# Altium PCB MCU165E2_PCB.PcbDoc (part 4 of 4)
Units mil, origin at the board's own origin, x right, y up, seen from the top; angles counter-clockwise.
Board outline 2658.83 x 2179.35 mil, 6 copper layers (Top Signal Layer, GND1, Mid Layer, PWR, GND2, Bottom Signal Layer), stack 60.4 mil thick; 226 components, 197 nets, 947 pads, 562 vias.
Unrouted connection lines stored in the file: 81.

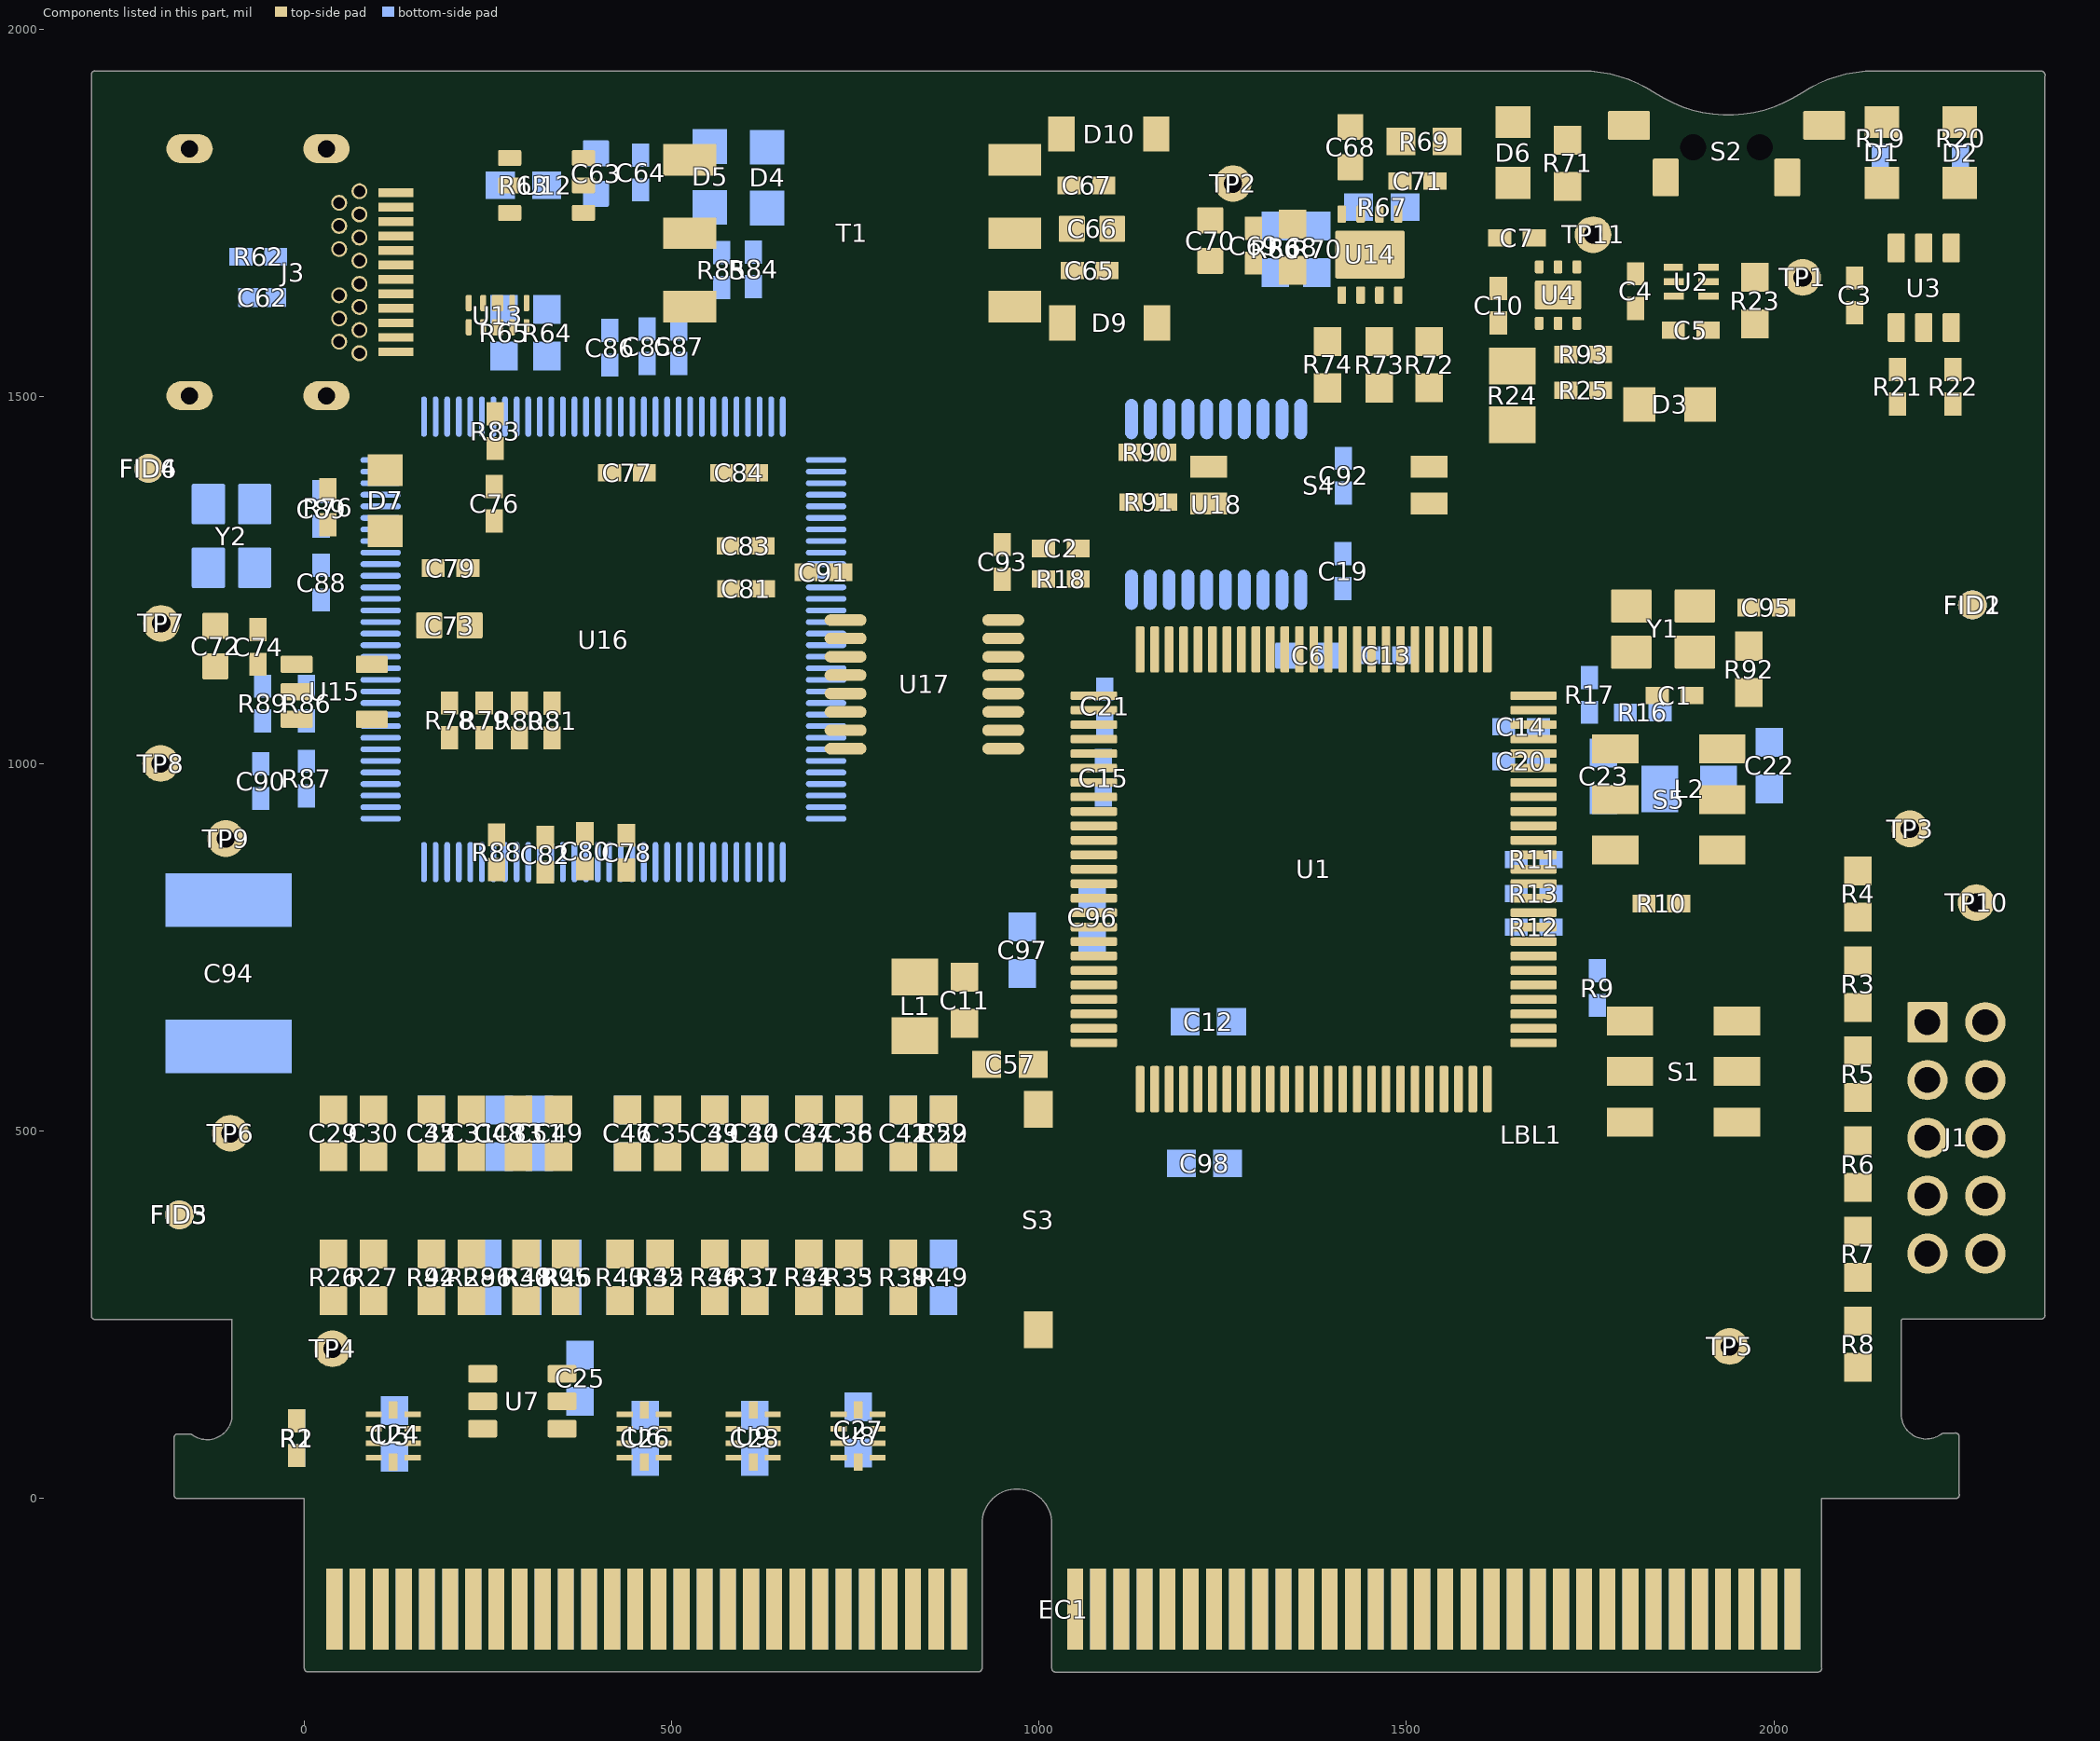
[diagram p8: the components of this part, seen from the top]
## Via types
v1: diameter 19.68, hole 9.84, Top Signal Layer to Bottom Signal Layer, tented both sides, 540 vias
v2: diameter 23.62, hole 11.81, Top Signal Layer to Bottom Signal Layer, tented both sides, 16 vias
v3: diameter 19.68, hole 7.99, Top Signal Layer to Bottom Signal Layer, tented bottom, 4 vias
v4: diameter 19.68, hole 7.87, Top Signal Layer to Bottom Signal Layer, tented bottom, 2 vias

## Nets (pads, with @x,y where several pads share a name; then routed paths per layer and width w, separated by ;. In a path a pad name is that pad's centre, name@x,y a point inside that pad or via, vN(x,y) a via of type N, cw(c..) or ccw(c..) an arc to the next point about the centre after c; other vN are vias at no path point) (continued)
pads on no net: EC1.4 EC1.32 EC1.41 EC1.42 EC1.43 EC1.44 EC1.66 EC1.110 EC1.113 EC1.114 EC1.115 EC1.116 EC1.117 FID1.1 FID2.1 FID3.1 FID4.1 FID5.1 FID6.1 J1.9 J3.A2 J3.A3 J3.A8 J3.A10 J3.A11 J3.B2 J3.B3 J3.B8 J3.B10 J3.B11 LBL1.0 S2. U2.6 U4.7@1688.57,1637.76 U4.7@1724,1637.76 U5.4 U5.9 U6.4 U6.9 U7.6 U8.4 U8.9 U9.4 U9.8 U9.9 U13.3@263.14,1594.13 U13.8@263.14,1627 U14.9@1425.58,1692.88 U14.9@1475.19,1692.88 U16.1 U16.2 U16.5 U16.6 U16.11 U16.12 U16.13 U16.14 U16.15 U16.18 U16.19 U16.20 U16.21 U16.22 U16.23 U16.24 U16.25 U16.27 U16.29 U16.30 U16.31 U16.32 U16.41 U16.42 U16.43 U16.44 U16.45 U16.46 U16.49 U16.50 U16.53 U16.54 U16.56 U16.57 U16.65 U16.67 U16.71 U16.72 U16.73 U16.74 U16.75 U16.76 U16.77 U16.78 U16.81 U16.82 U16.83 U16.84 U16.85 U16.86 U16.91 U16.92 U16.95 U16.102 U16.103 U16.104 U16.105 U16.106 U16.107 U16.108 U16.109 U16.110 U16.111 U16.112 U16.116 U16.117 U16.118 U16.119 U16.120 U16.121 U16.123 U16.124 U16.125 U16.126 U16.127 U16.128 U18.3 U18.5

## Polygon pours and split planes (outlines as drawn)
EMU_GND on GND1 "GND1_EMU_GND_P002" (solid, remove dead copper, pour order 2): -263.59,1927.66 768,1927.66 768,946.16 619.85,798 -265.76,798
GND on GND1 "GND1-GND" (solid, remove dead copper, pour order 34): 928,1947 928,888 680,640 -290.58,640 -290.58,242.58 -286,238 -100,238 -100,118 -96,114 -126,84 -126,80 -174,80 -177,83 -177,1 -3.04,1 -1,-1.04 -1,-241 2054.73,-241 2067,-228.73 2067,-0.11 2255.11,-0.11 2253,2 2253,88 2219,88 2211,80 2192,80 2175,97 2175,244.19 2364.19,244.19 2369,249 2369,1941 2363,1947 929,1947
EMU_5V0 on PWR "PWR_EMU_5V0_P006" (solid, remove dead copper, pour order 6): -264.49,1917.16 761,1917.16 761,1589.15 733.01,1561.16 190.16,1561.16 -48,1323 -48,1082 -68,1062 -236,1062 -262.82,1088.82 -262.74,1913.9
VDD_1V2 on PWR "PWR-No Net 1" (solid, remove dead copper, pour order 54): 1616,209.78 1616,113 1623.45,105.55 1730.45,105.55 1939,-103 1949,-113 2025,-113 2034,-104 2034,-72.82 1957.32,3.86 1957.32,149.68 1931,176 1851.42,176 1838.42,189 1772.18,189 1679.18,282 1633.1,282 1620.16,282 1603.92,265.76 1603.92,219 1606.78,219
3V3 on PWR "PWR-3V3" (solid, remove dead copper, pour order 20): 1148.99,1266.6 1066.72,1184.33 1066.72,969.47 974.21,876.96 974.21,794.21 870,690 870,668 845,643 683,643 914.85,874.85 914.85,1465.09 993.25,1543.49 1743.57,1543.49 1838,1637.92 1838,1853.1 1859.71,1874.81 2334,1874.81 2334,88.13 2267.87,22 2068.46,22 2067,23.46 2046,2.46 2046,-27 2027,-46 2009,-46 1964,-1 1964,133 1964,175.98 1755.54,384.44 1755.54,1266.6
VDD_1V2 on PWR "PWR-VDD_1V2" (solid, remove dead copper, pour order 30): 1529.46,408.54 1445,493 1445,528 1347,626 1347,629 1309,629 1254,629 1194.43,688.57 1194.43,810.03 1093.39,911.07 1093.39,1047.83 1142.64,1097.08 1745.19,1097.08 1745.19,355.02 1940.32,159.89 1940.32,105.55 1623.3,105.55 1576.52,152.33 1529.46,199.39
EMU_3V3 on PWR "PWR-No Net" (solid, remove dead copper, pour order 8): -290.79,798 619.85,798 774,952.15 774,1495 723,1546 201,1546 -24,1321 -24,1079.29 -57.29,1046 -286.12,1046 -291.12,1041
ISO_Pout_5V0 on PWR "PWR_ISO_POUT_5V0_P056" (solid, remove dead copper, pour order 56): 1104.2,1913 1076.52,1885.32 1076.52,1833.73 1094.5,1815.75 1505.14,1815.75 1513.53,1824.14 1513.53,1897.03 1497.56,1913
5V0 on PWR "PWR_5V0_P058" (solid, remove dead copper, pour order 58): 1561.53,1850.06 1543.49,1832.02 1543.49,1663.96 1551.87,1655.58 1784.24,1655.58 1814.03,1685.37 1814.03,1842.19 1806.16,1850.06
VDDIO_3V3 on PWR "PWR_VDDIO_3V3_P026" (solid, remove dead copper, pour order 26): 1084.77,1057.96 1096.91,1045.82 1174.29,1045.82 1241.1,1112.63 1611.63,1112.63 1624.42,1099.84 1624.42,982.4 1685.6,921.22 1738,921.22 1769.97,953.19 1769.97,1223.26 1737.69,1255.54 1151.49,1255.54 1084.77,1188.82
VDDA_3V3 on PWR "PWR_VDDA_3V3_P014" (solid, remove dead copper, pour order 14): 831.34,607.61 1125.77,607.61 1255.04,736.88 1348.85,736.88 1465.5,620.23 1465.5,470.95 1456.55,462 896.75,462 818.98,539.77 818.98,598.84
HSEC_5V0 on PWR "PWR-HSEC_5V0" (solid, remove dead copper, pour order 16): 490,580 490,581 738.56,581 771.71,614.15 865.52,614.15 1120.02,614.15 1219.24,713.37 1219.24,789.39 1088.72,919.91 1010.65,919.91 996.7,905.96 996.7,899.68 963,860 961,857 950,857 950,832 874,756 874,718 786,718 785.5,718.5 705,638 6,638 -75,557 -75,51 -37,13 0,13 0,-196 32.97,-228.97 854.03,-228.97 886,-197 886,-76.37 886.86,-11.9 919.07,18.93 937.29,37.15 996.7,37.15 1036,-2.15 1036,-90.41 1058.59,-113 1883.29,-113 1894.59,-101.7 1894.59,-76.59 1720,98 1615,98 1539.83,173.17 1420.83,173.17 1415,179 937,179 934,182 834.51,82.51 832.49,82.51 702,-47 596,-47 593,-44 210,-44 168.15,-2.15 119.15,-2.15 41.83,75.17 41.83,176.17 10,208 10,533.4 56.6,580
VDDA_3V3 on PWR "PWR-VDDA_3V3" (solid, remove dead copper, pour order 12): 495,579 1377.07,579 1444,512.07 1444,481.73 1512.87,412.59 1512.87,194.36 1496.51,178 954.96,178 848,71.04 745,-31.96 745,-102 734,-113 189,-113 171.63,-95.63 171.63,-52.75 47,71.88 47,172 2,217 2,525.4 55.6,579
ISO_Pout_5V0 on Top Signal Layer "TOP_SIGNAL_LAYER_ISO_POUT_5V0_P010" (solid, remove dead copper, pour order 10): 1066.33,1586.96 1087.82,1565.46 1162.46,1565.46 1171.46,1574.46 1171.46,1916.59 1169.58,1918.47 1094.46,1918.46 1066.33,1890.33
EMU_GND on Top Signal Layer "TOP_SIGNAL_LAYER_EMU_GND_P050" (solid, remove dead copper, pour order 50): -263.59,1927.66 768,1927.66 768,946.16 619.85,798 -265.76,798
GND on Top Signal Layer "Top Signal Layer-GND" (solid, remove dead copper, pour order 62): 930.87,1940.66 930.87,882.87 681.66,633.66 -287.71,633.66 -287.71,236.24 -283.13,231.66 -97.13,231.66 -97.13,111.66 -93.13,107.66 -123.13,77.66 -123.13,73.66 -171.13,73.66 -174.13,76.66 -174.13,-5.34 -0.17,-5.34 1.87,-7.37 1.87,-247.34 2057.59,-247.34 2069.87,-235.06 2069.87,-6.45 2257.98,-6.45 2255.87,-4.34 2255.87,81.66 2221.87,81.66 2213.87,73.66 2194.87,73.66 2177.87,90.66 2177.87,237.86 2367.06,237.86 2371.87,242.66 2371.87,1934.66 2365.87,1940.66 931.87,1940.66
EMU_GND on Mid Layer "MID_LAYER_EMU_GND_P042" (solid, remove dead copper, pour order 42): -263.59,1927.66 768,1927.66 768,946.16 619.85,798 -265.76,798
HSEC_5V0 on Mid Layer "Mid Layer-HSEC_5V0" (solid, remove dead copper, pour order 32): 921.49,846.51 932.13,835.87 1182.87,835.87 1188,841 1188,1851.81 1160.81,1879 942.29,1879 921.49,1858.21
EMU_GND on GND2 "GND2_EMU_GND_P036" (solid, remove dead copper, pour order 36): -263.59,1927.66 768,1927.66 768,946.16 619.85,798 -265.76,798
GND on GND2 "GND2-GND" (solid, remove dead copper, pour order 40): 928,1947 928,888 680,640 -290.58,640 -290.58,242.58 -286,238 -100,238 -100,118 -96,114 -126,84 -126,80 -174,80 -177,83 -177,1 -3.04,1 -1,-1.04 -1,-241 2054.73,-241 2067,-228.73 2067,-0.11 2255.11,-0.11 2253,2 2253,88 2219,88 2211,80 2192,80 2175,97 2175,244.19 2364.19,244.19 2369,249 2369,1941 2363,1947 929,1947
EMU_GND on Bottom Signal Layer "BOTTOM_SIGNAL_LAYER_EMU_GND_P052" (solid, remove dead copper, pour order 52): -260.52,1943.12 771.07,1943.12 771.07,961.62 608.45,799 -262.72,799
GND on Bottom Signal Layer "Bottom Signal Layer-GND" (solid, remove dead copper, pour order 60): 928,1947 928,888 680,640 -290.58,640 -290.58,242.58 -286,238 -100,238 -100,118 -96,114 -126,84 -126,80 -174,80 -177,83 -177,1 -3.04,1 -1,-1.04 -1,-241 2054.73,-241 2067,-228.73 2067,-0.11 2255.11,-0.11 2253,2 2253,88 2219,88 2211,80 2192,80 2175,97 2175,244.19 2364.19,244.19 2369,249 2369,1941 2363,1947 929,1947

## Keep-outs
Keep-Out Layer:
  lines w7.87: 1737,1943 -284.72,1942.99 ccw(c-284.72,1937.99) -289.73,1937.99 -289.73,248.71 ccw(c-284.72,248.71) -284.72,243.7 -98.32,243.7 -98.32,115.84 cw(c-124,114.26) -98.27,113.93 cw(c-132.25,113.92) -152.76,86.83 ccw(c-155.74,82.96) -155.78,87.84 -172.11,87.84 ccw(c-172.15,82.91) -175.66,86.37 ccw(c-172.11,82.73) -177.19,82.76 -177.19,4.84 ccw(c-172.19,4.83) -171.02,-0.04 0.06,-0.04 0.06,-231.05 ccw(c5.07,-231.05) 5.9,-236 917.4,-236 ccw(c917.4,-230.98) 922.42,-230.98 922.42,-34.1 cw(c969.9,-34.49) 1017.39,-34.1 1017.39,-231.27 ccw(c1022.39,-231.28) 1018.85,-234.82 ccw(c1022.51,-231.22) 1022.46,-236.35 2060.22,-236.28 ccw(c2060.22,-231.26) 2065.23,-231.26 2065.16,-230.44 2065.16,-0.11 2247.39,-0.11 ccw(c2247.39,4.91) 2252.41,4.91 ccw(c2247.65,4.92) 2252.2,6.32 ; 1738,1943 cw(c1738,1761.33) 1838,1913 ccw(c1938,2064.67) 2038,1913 cw(c2138,1761.33) 2138,1943 2363.01,1943 cw(c2362.92,1936.82) 2369,1935.72 2369,249.2 cw(c2364,249.2) 2364,244.19 2174.88,244.19 2173.42,242.73 2173.42,114.71 ccw(c2207.4,114.83) 2227.9,87.73 ; 2227.9,87.72 cw(c2230.91,83.8) 2230.93,88.74 2245.21,88.74 cw(c2247.2,84.13) 2252.2,84.13 2252.2,6.33
  text ".Layer_Name" at -3605.96,-2857.09 h60

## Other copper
Top Signal Layer:
  pour cut-out: 717.58,294.2 710.51,294.2 707.35,291.03 705.7,291.03 705.7,281.5 713.9,273.3 718.73,273.3 718.73,274.42 723.13,278.82 722.94,279.01 722.94,287.47 723.04,287.57
  pour cut-out: 710.51,311.44 710.51,294.2 709.08,292.76 692.26,292.76 692.26,304.88 685.87,311.27
  pour cut-out: 16.11,357.26 16.11,244.89 117.97,244.89 117.97,357.25
  pour cut-out: 2168.19,1434.65 2243.2,1434.65 2231.04,1446.81 2231.04,1457.24 2192.82,1457.24 2187.39,1451.81
  pour cut-out: 2260.27,1557.52 2260.27,1510.27 2151.38,1510.13 2151.38,1569.96 2157.32,1575.9 2258.35,1575.9 2258.35,1559.44
  pour cut-out: 1148.95,1293.4 1148.95,1318.66 1138.63,1328.98 1122.61,1328.98 1110.89,1317.26 1110.89,1302.87 1115.34,1298.42
  pour cut-out: 1293.6,1423.94 1298.07,1419.46 1298.07,1372.26 1285,1359.19 1254.82,1359.19 1254.82,1414.97 1252.36,1417.43 1258.87,1423.94
  pour cut-out: 2164.32,289.95 2162.6,291.67 2150.19,291.67 2150.19,303.26 2155.96,309.03 2156.93,308.06 2171.39,308.06 2171.39,300.07 2172.71,298.75 2164.32,290.36
  pour cut-out: 2138.05,216.86 2138.05,203.23 2118.32,203.23 2115.25,206.3 2118.09,209.14 2118.09,218.81
  pour cut-out: 322.26,553.18 322.26,440.82 424.13,440.82 424.13,553.18
  pour cut-out: 470.72,553.18 470.72,440.82 572.59,440.82 572.59,553.18
  pour cut-out: 589.18,553.18 589.18,440.82 691.05,440.82 691.05,553.18
  pour cut-out: 717.64,553.18 717.64,440.82 897.07,440.82 897.07,553.18
  pour cut-out: 663.18,553.18 663.18,440.82 765.04,440.82 765.04,553.18
  pour cut-out: 534.72,553.18 534.72,440.82 636.58,440.82 636.58,553.18
  pour cut-out: 416.25,553.18 416.25,440.82 518.12,440.82 518.12,553.18
  pour cut-out: 267.79,553.18 267.79,440.82 369.66,440.82 369.66,553.18
  pour cut-out: 149.33,553.18 149.33,440.82 251.2,440.82 251.2,553.18
  pour cut-out: 16.11,553.18 16.11,440.82 117.97,440.82 117.97,553.18
  region net ISO_Pout_5V0: 1130.29,1896.55 1130.29,1825.69 1141.94,1814.04 1155.88,1827.98 1171.46,1827.98 1171.46,1886.02 1160.8,1896.68 1144.32,1896.68
  pour cut-out: 1026.79,1309.74 1037.32,1309.74 1037.32,1258.84 1021.72,1258.84 1021.72,1309.63
  pour cut-out: 1104.38,1440.48 1104.38,1331.76 1105.22,1330.92 1173.51,1330.92 1173.51,1440.48
  region net GND: 1408.09,1725.18 1532.31,1725.18 1540.67,1716.82 1540.67,1672.52 1528.84,1660.69 1384.45,1660.69 1371.83,1673.31 1375.3,1676.78 1375.3,1717.92 1382.54,1725.16 1406.56,1725.16
  region net GND: 1661.26,1662.02 1654.11,1654.87 1654.11,1621.74 1661.84,1614.01 1757.92,1614.01 1760.7,1616.79 1760.7,1651.46 1750.14,1662.02
  region net 3V3: 1612.68,1482.55 1612.68,1436.9 1608.15,1432.37 1608.15,1412.17 1611.33,1408.99 1686.1,1408.99 1690.04,1412.93 1690.04,1425.14 1675.46,1439.72 1675.46,1478.02 1671.18,1482.3
  region net VDDA_3V3: 850.17,662.7 792.62,662.7 775.26,645.34 775.26,591.94 781.27,585.93 842.7,585.93 862.33,605.56 862.33,656.4 855.96,662.77
  region net 3V3: 824.19,770.62 887.67,770.62 912.76,745.53 912.76,689.39 907.37,684 802.56,684 794.92,691.64 794.92,741.35
  region net 5V0: 1868.84,1660.87 1846.95,1660.87 1837.07,1670.75 1819.58,1670.75 1815.6,1666.77 1831.27,1651.1 1867.06,1651.1 1868.82,1652.86
  region net NetC10_1: 1659.98,1608.22 1652.69,1615.51 1613.82,1615.51 1612.12,1613.81 1612.12,1518.43 1614.01,1516.54 1675.43,1516.54 1695.18,1496.79 1729.78,1496.79 1732.8,1499.81 1732.8,1568.37 1721.33,1579.84 1694.96,1579.84 1686.52,1588.28 1686.52,1606.55 1684.85,1608.22
  region net 5V0: 1767.97,1744.87 1784.37,1744.87 1837.07,1692.17 1837.07,1656.9 1831.27,1651.1 1798.39,1651.1 1782.06,1667.43 1733.85,1667.43 1730.91,1670.37 1730.91,1731.23 1744.57,1744.89
  region net 5V0: 1684.78,1667.37 1673.08,1667.37 1658.21,1682.24 1658.21,1727.09 1675.99,1744.87 1767.97,1744.87 1780.98,1731.86 1780.98,1706.5 1769.38,1694.9 1743.83,1694.9 1737.74,1688.81 1737.74,1677.75 1736.14,1676.15 1727.2,1676.15 1726.02,1677.33 1726.02,1694.48 1720.94,1699.56 1692.86,1699.56 1686.58,1693.28 1686.58,1669.82 1686.22,1669.46
  region net ISO_Pout_5V0: 1457.29,1799.31 1457.29,1894.96 1463.58,1901.25 1509.02,1901.25 1512.24,1898.03 1512.24,1783.35 1507.09,1778.2 1461.69,1778.2 1457.24,1782.65
  region net POWER_SWITCH_OUT: 1380.06,1820.55 1377.19,1817.68 1377.19,1782.19 1383.74,1775.64 1424.63,1775.64 1428.2,1772.07 1431.25,1775.12 1431.25,1804.2
  region net ISO_Pout_5V0: 1457.29,1742.08 1457.29,1799.31 1462.91,1804.93 1506.26,1804.93 1507.09,1804.1 1507.09,1778.2 1498.23,1769.34 1478.93,1769.34 1469.08,1759.49 1469.08,1742.87 1468.3,1742.09
  region net POWER_SWITCH_OUT: 1443.47,1739.58 1443.47,1779.81 1443.47,1826.02 1440.12,1829.37 1388.88,1829.37 1380.06,1820.55 1380.06,1807.86 1431.55,1756.37 1431.55,1742.13 1434.31,1739.37
  region net HSEC_5V0: 1231.41,1815 1215,1798.59 1215,1725 1219,1721 1320.52,1721 1326,1715.52 1365.52,1715.52 1386.47,1736.47 1417,1736.47 1418,1737.47 1418,1758.02 1416.23,1759.79 1375.49,1759.79 1320.28,1815
  pour cut-out: 1022.42,-205.82 1022.42,-238.18 2053,-238.18 2053,-205.82
  pour cut-out: 6.24,-206 6.24,-238.36 917.51,-238.36 917.51,-206
  pour cut-out: 2082.06,263.81 2093.68,263.81 2093.68,275.4 2092.57,276.51 2082.06,276.51
  pour cut-out: 354.59,1065 354.59,1012.34 355.92,1011 355.55,1010.63 179.86,1010.63 179.86,1063.46 181.4,1065
  region net EMU_5V0: 151,1625 165,1639 199,1639 209.58,1628.42 209.58,1599.58 202,1592 171,1592 151,1612 151,1621
  region net EMU_5V0: 215,1711 231.78,1727.78 231.78,1759.98 222.75,1769 193,1769 148,1724 148,1714 151,1711
  region net GND: 931,1660 1053.49,1660 1061,1667.51 1061,1793 1054,1800 1025.04,1800 995.04,1770 931.78,1770 923,1761.22 923,1668
  region net NetD9_2: 921.49,1636.1 921.49,1567.01 928.5,1560 1038,1560 1048.43,1570.43 1048.43,1621 1020.43,1649 934.39,1649
  region net NetD10_2: 923,1886 923,1791.52 933.52,1781 991.14,1781 1053,1842.86 1053,1879.33 1038.33,1894 931,1894
  region net NetT1_6: 354,1756.73 354,1655 421,1588 508,1588 516,1596 516,1637 505,1648 462.73,1648 417,1693.73 417,1743.7 396.7,1764 361.27,1764
  region net NetT1_4: 359,1814 365,1808 413.04,1808 432.04,1789 539,1789 548,1798 548,1844 536,1856 363.04,1856 359,1851.96
  text ".Layer_Name" at -3605.96,-2857.09 h60
Mid Layer:
  pour cut-out: 1036.29,845.24 1036.29,827.56 1038.01,825.84 1038.07,825.9 1069.38,825.9 1069.38,849.51 1065.99,846.12 1043.62,846.12
  region net MCU_PGA3_IN_N: 466.93,374.64 474.75,366.82 493.93,366.82 501.75,374.64
  region net MCU_PGA1_IN_N: 902.33,500.64 902.33,491.65 903.22,490.76 921.38,508.92 921.95,508.92 926.74,513.71 916.9,513.71 909.95,506.76
  text ".Layer_Name" at -3625.56,-2847.9 h60
PWR:
  region net 3V3: 2260.67,333.36 2260.67,277.67 2315.21,277.67 2315.21,333.16
  region net VDD_1V2: 1926.66,209.63 1893.82,176.79 1893.82,156.02 1936.56,156.02 1950.11,142.47 1957.22,149.58 1957.22,206.71 1939.77,206.88
  region net VDDA_3V3: 831.34,607.61 778.84,607.68 765.06,593.9 765.06,566.19 771.02,560.23 852.54,560.23 854.15,561.84 854.15,584.8
  region net VDDIO_3V3: 1624.57,1006.99 1614.47,996.89 1599.61,996.89 1594.16,991.44 1594.16,981.58 1600.39,975.35 1631.47,975.35 1643.84,987.72
  text ".Layer_Name" at -3601.06,-2848 h60
GND1:
  text ".Layer_Name" at -3618.06,-2847 h60
GND2:
  text ".Layer_Name" at -3606.06,-2848 h60
Bottom Signal Layer:
  pour cut-out: 589.18,490.19 582.12,490.19 576.55,484.62 576.55,462.86 586.25,462.86 596.3,452.81 607.99,464.5 607.99,467.63
  pour cut-out: 277.73,357.19 277.73,244.83 893.44,244.83 893.44,357.19
  pour cut-out: -27.19,37.69 -27.19,14.84 -17.13,4.78 -15.24,6.67 11.34,6.67 11.34,31.66 8.44,34.56
  region net HSEC_PGA3_IN_P: 315.16,95.32 304.91,105.57 301.84,105.57 301.84,85.64 303.83,83.65
  region net HSEC_PGA3_IN_N: 279.25,95.13 287.83,103.71 292.57,103.71 292.57,85.45 290.58,83.46
  region net 5V0: 1478.35,1775.82 1575.46,1775.82 1581.29,1769.99 1581.29,1730.18 1573.07,1721.96 1491.34,1721.96 1478.2,1735.1
  region net POWER_SWITCH_OUT: 1382.4,1814.33 1447.23,1814.33 1454.38,1807.18 1454.38,1740.67 1452.17,1738.46 1417.6,1738.46 1415.92,1740.14 1415.92,1760.74 1396.58,1780.08 1380.62,1780.08 1373.39,1787.31 1373.39,1805.32
  text ".Layer_Name" at -3605.96,-2857.09 h60
Multi-Layer:
  pour cut-out: 738.26,-62.43 738.26,-114.26 740.39,-116.39 748.43,-116.39 748.43,-62.42
  pour cut-out: 1038.16,857.59 1036.29,855.73 1036.29,845.24 1039.38,842.15 1166.48,842.15 1372.64,635.99 1449.74,635.99 1462.25,623.48 1462.25,467.7 1173.54,178.99 979.85,178.99 738.34,-62.52 744.79,-68.96 982.73,168.98 1178.76,168.98 1473.99,464.21 1473.99,626.35 1451.67,648.67 1378.22,648.67 1169.3,857.59
  pour cut-out: 2164.32,691.53 2332.43,691.53 2332.43,289.95 2164.32,289.95

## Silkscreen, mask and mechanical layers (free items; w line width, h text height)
Top Overlay:
  text "HSEC_5V0" at 1210.43,1823.81 h43
  text "5V0" at 1780.2,1735.13 h43
  text "XRSn" at 1878.25,1705.84 h80
  text "JTAG" at 1573.59,1357.29 h60
  text "UART" at 1574.86,1300.26 h60
  text "EMU_5V0" at -255,1232 h51.18
  text "EMU_3V3" at -157,985 h51.18
  text "------- --------- -------- -" at 792,965 h35 r90
  text "VDDIO_3V3" at 2035.78,949.09 h51.18
  text "------------------ --------- -" at 931,906 h35 r90
  text "3V3" at 2245.77,848.42 h51.18
  text "EMU_GND" at -196,827 h51.18
  text "-------" at 619,779 h35 r45
  text "-------------------------" at -267,774 h35
  text "Boot" at 1817.53,700.68 h80
  text "1" at 1988.94,695.41 h60
  text "1" at 1754.67,693.95 h60
  text "----------" at 690,639 h35 r45
  text "---------------------------" at -273,626 h35
  text "GND" at -141,538 h51.18
  text "GPIO32" at 2027.26,501.21 h60 r90
  text "GPIO24" at 1762.55,495.21 h60 r90
  text "INT" at 1063.46,467.29 h65
  text "0" at 915.89,459.5 h60
  text "0" at 1748.24,441.4 h60
  text "0" at 1985.78,439.32 h60
  text "1" at 920.65,246.01 h60
  text "EXT" at 1066.84,226.95 h65
  text "VREFHI" at 932.33,143.86 h65
  text "VDD_1V25" at 1830.07,143.78 h51.18
  text "VDDA_3V3" at -67.82,142.14 h47.24
  text "TMDSCNCD28P551X / MCU165E2" at 1245.16,3.47 h60
  text "1" at 38,-5 h40
  text "55" at 870,-9.57 h40
  text "57" at 1038.19,-9.57 h40
  text "119" at 1982.22,-13 h40
  text ".Layer_Name" at -3605.96,-2857.09 h60
Bottom Overlay:
  text "C2000 F28P551x controlCARD" at 1733.73,1863 h60
  text "----------------------------" at 793,966 h35 r90
  text "------------------------------" at 929,895 h35 r90
  text "-------" at 624,776 h35 r45
  text "--      -----------------" at -272,775 h35
  text "----------" at 687,631 h35 r45
  text "--      -------------------" at -271,626 h35
  text "58" at 1068.13,2.5 h40
  text "2" at 56,-5 h40
  text "56" at 908.18,-9 h40
  text "120" at 2033,-13 h40
  text ".Layer_Name" at -3605.96,-2857.09 h60
Top Paste:
  text ".Layer_Name" at -3605.96,-2857.09 h60
Bottom Paste:
  text ".Layer_Name" at -3603.94,-2855.08 h60
Top Solder:
  text ".Layer_Name" at -3605.96,-2857.09 h60
  text ".Layer_Name" at -3605.96,-2857.09 h60
Bottom Solder:
  text ".Layer_Name" at -3605.96,-2857.09 h60
Drill Guide:
  text ".Layer_Name" at -3605.96,-2857.09 h60
M1 Board Outline:
  lines w8: -289.73,1935.72 -289.73,248.71 ccw(c-284.72,248.71) -284.72,243.7 -98.73,243.7 ; -289.73,1937.99 cw(c-284.72,1937.99) -284.72,1943.01 1737,1943 ; -98.32,243.7 -98.32,115.84 cw(c-124,114.26) -98.27,113.93 cw(c-132.25,113.92) -152.76,86.83 ccw(c-155.74,82.96) -155.78,87.84 -172.11,87.84 ccw(c-172.15,82.91) -175.66,86.37 ccw(c-172.11,82.73) -177.19,82.76 -177.19,4.84 ccw(c-172.19,4.83) -171.02,-0.04 0.06,-0.04 0.06,-231.05 ccw(c5.07,-231.05) 5.9,-236 917.51,-236 ccw(c917.51,-230.98) 922.53,-230.98 ccw(c917.77,-230.97) 922.31,-229.57 922.32,-35.08 922.42,-34.1 cw(c969.9,-34.49) 1017.39,-34.1 1017.39,-231.27 ccw(c1022.39,-231.28) 1018.85,-234.82 ccw(c1022.51,-231.22) 1022.46,-236.35 2060.22,-236.28 ccw(c2060.22,-231.26) 2065.23,-231.26 2065.16,-230.44 2065.16,-0.11 2247.39,-0.11 ccw(c2247.39,4.91) 2252.41,4.91 ccw(c2247.65,4.92) 2252.2,6.32 ; 1738,1943 cw(c1738,1761.33) 1838,1913 ccw(c1938,2064.67) 2038,1913 cw(c2138,1761.33) 2138,1943 ; 2140,1942.99 2361,1943 ; 2227.9,87.72 cw(c2230.91,83.8) 2230.93,88.74 2245.21,88.74 cw(c2247.2,84.13) 2252.2,84.13 2252.2,6.33 ; 2227.9,87.73 cw(c2207.4,114.83) 2173.42,114.71 2173.42,242.73 2174.88,244.19 2362.35,244.19 ; 2363.01,1943 cw(c2362.92,1936.82) 2369,1935.72 2369,248.71 ; 2364,244.19 ccw(c2364,249.2) 2369.01,249.2
  text ".Layer_Name" at -3593,-2846 h60
M2 Board Dimensions:
  rectangle: -4057.96,-2398.6 -3682.96,-2273.6
  rectangle: -4182.96,-2273.6 -4057.96,-2148.6
  lines w7: -4182.96,-2273.6 -3182.96,-2273.6 ; -4057.96,-2398.6 -4057.96,-2148.6 ; -3932.96,-2398.6 -3932.96,-2148.6 ; -3682.96,-2398.6 -3682.96,-2148.6 ; -3432.96,-2398.6 -3432.96,-2148.6 ; -4182.96,-2398.6 -4182.96,-2148.6 -3182.96,-2148.6 -3182.96,-2398.6 -4182.96,-2398.6
  lines w10: -3201.06,-523 -3133.06,-523 ; -3159.06,-552 -3132.06,-524 ; -3159.06,-493 -3132.06,-523 ; -3125.06,822 -3057.06,904 ; -3123.06,-570 -3123.06,-248 ; -3123.06,-207 -3073.06,-261 -2963.06,-261 -2916.06,-204 ; -3123.06,-205 -3123.06,825 ; -3058.06,905 -2994.06,818 ; -3040.06,-355 -2972.06,-355 ; -2998.06,-384 -2971.06,-356 ; -2998.06,-325 -2971.06,-355 ; -2993.06,817 -2921.06,907 ; -2962.06,-570 -2962.06,-288 ; -2916.06,-205 -2916.06,825 -2916.06,910 ; -2915.06,-570 -2915.06,-248 ; -2909.09,445.62 cw(c-2965.06,-262) -2525.72,295.54 ; -2907.21,444.26 ccw(c-2767.46,678.92) -2856.34,420.66 ; -2907.06,-520 -2880.06,-550 ; -2907.06,-519 -2880.06,-491 ; -2907.06,451 cw(c-2874.6,277.02) -2844.34,451.39 ; -2905.06,-519 -2837.06,-519 ; -2905.06,-356 -2878.06,-386 ; -2905.06,-355 -2878.06,-327 ; -2903.06,-355 -2835.06,-355 ; -2889.06,-166 -2426.06,406 ; -2579.06,310 ccw(c-2441.53,650.43) -2524.39,292.74 ; -2561.81,343.3 cw(c-2678.66,209.86) -2523.06,295 ; -247.06,145 -197.66,145 -110.66,232 ; -184.06,-164 -164.66,-164 -12.66,-12 ; -130.66,232 -110.66,232 ; -110.66,212 -110.66,232 ; -32.66,-12 -12.66,-12 ; -12.66,-32 -12.66,-12 ; 2074.94,-31.6 2074.94,-11.6 ; 2094.94,-11.6 2074.94,-11.6 ; 2183.94,212.4 2183.94,232.4 ; 2203.94,232.4 2183.94,232.4 ; 2246.34,-163.6 2226.94,-163.6 2074.94,-11.6 ; 2504,-53 2469.34,-53 2183.94,232.4
  text "30" at -2720.06,466 h60
  text "R 39.00" at -659.06,118 h60
  text "R 39.00" at 2528,-79 h60
  text "R 39.00" at -599.06,-198 h60
  text "R 39.00" at 2281.94,-199 h60
  text "18MIL" at -2794.06,-383 h60
  text "62MIL" at -2801.06,-547 h60
  text "GOLD FINGER" at -3282.06,-784 h60
  text "SIDE VIEW" at -3228.06,-897 h60
  text ".Layer_Name" at -3605.96,-2857.09 h60
M3 3D STEP Top:
  text ".Layer_Name" at -3605.96,-2857.09 h60
M4 3D STEP Bottom:
  text ".Layer_Name" at -3605.96,-2857.09 h60
M5 Assembly Top:
  lines w10: -4474.96,-2928.77 2125.04,-2928.77 ; -4474.96,-2725.43 2127.04,-2725.43 ; -4474.96,-2522.1 -4474.96,-3132.1 -469.96,-3132.1 2127.04,-3132.1 2127.04,-2522.1 -4474.46,-2522.1 -4474.46,-3132.1 -2898.96,-3132.1 ; -2009.96,-3132.1 -2009.96,-2522.1 ; -742.96,-2725.43 -742.96,-2522.1 ; 97.04,-2725.43 97.04,-2522.1 ; 719.04,-3138.6 719.04,-2935.77
  text "COMPONENTS MARKED 'DNP' SHOULD NOT BE POPULATED." at -3029.46,-2317.1 h60
  text "ASSEMBLY VARIANT:" at -3029.96,-2432.6 h60
  text ".VariantName" at -1993.96,-2432.6 h60
  text "PCB VIEWED FROM TOP SIDE" at -4411.46,-2654.27 h60
  text "BOARD #:" at -1934.96,-2654.27 h60
  text ".PRJ_Number" at -1389.46,-2654.27 h60
  text "REV:" at -544.96,-2654.27 h60
  text ".PCB_Rev" at -253.46,-2654.27 h60
  text "SVN REV:" at 293.04,-2654.27 h60
  text ".VersionControl_RevNumber" at 799.04,-2654.27 h60
  text "TID #:" at -1934.96,-2857.6 h60
  text ".TID" at -1389.46,-2857.6 h60
  text "PLOT NAME =" at -4411.46,-3062.94 h60
  text ".plot_File_Name" at -3605.96,-3062.94 h60
  text "GENERATED    :" at -1932.96,-3062.94 h60
  text ".Print_Date" at -1063.46,-3062.94 h60
  text ".Print_Time" at -334.46,-3062.94 h60
  text "TEXAS INSTRUMENTS" at 930.04,-3062.94 h60
M6 Assembly Bottom:
  lines w10: -4475.46,-2725.93 2126.54,-2725.93 ; -4473.46,-2929.27 2126.54,-2929.27 ; -3067.46,-3139.1 -3067.46,-2936.27 ; -2445.46,-2725.93 -2445.46,-2522.6 ; -1605.46,-2725.93 -1605.46,-2522.6 ; -338.46,-3132.6 -338.46,-2522.6 ; 550.54,-3132.6 2126.04,-3132.6 2126.04,-2522.6 -4475.46,-2522.6 -4475.46,-3132.6 -1878.46,-3132.6 2126.54,-3132.6 2126.54,-2522.6
  text "COMPONENTS MARKED 'DNP' SHOULD NOT BE POPULATED." at 1919.04,-2316.6 h60
  text ".VariantName" at 875.04,-2432.6 h60
  text "ASSEMBLY VARIANT:" at 1914.04,-2432.6 h60
  text "SVN REV:" at -2641.46,-2654.77 h60
  text ".PCB_Rev" at -2094.96,-2654.77 h60
  text "REV:" at -1803.46,-2654.77 h60
  text ".PRJ_Number" at -958.96,-2654.77 h60
  text "BOARD #:" at -413.46,-2654.77 h60
  text "PCB VIEWED FROM BOTTOM SIDE" at 2063.04,-2654.77 h60
  text ".TID" at -958.96,-2858.1 h60
  text "TID #:" at -413.46,-2858.1 h60
  text "TEXAS INSTRUMENTS" at -3278.46,-3063.44 h60
  text ".Print_Time" at -2013.96,-3063.44 h60
  text ".Print_Date" at -1284.96,-3063.44 h60
  text "GENERATED    :" at -415.46,-3063.44 h60
  text ".plot_File_Name" at 1257.54,-3063.44 h60
  text "PLOT NAME =" at 2063.04,-3063.44 h60
M9 Title Sheet:
  drawing of 57 lines, arcs and shapes, not listed
  text "1" at -3443.12,6037.9 h70
  text "2" at -947.46,6037.9 h70
  text "3" at 1541.89,6037.9 h70
  text "4" at 4048.56,6037.9 h70
  text "5" at 6547.54,6037.9 h70
  text "6" at 9052.54,6037.9 h70
  text "A" at -4599.46,4894.9 h70
  text "A" at 10200.54,4894.9 h70
  text "B" at -4599.46,2514.9 h70
  text "B" at 10200.54,2514.9 h70
  text "C" at -4599.46,139.9 h70
  text "C" at 10200.54,139.9 h70
  text "PROJECT TITLE:" at 7160.54,-1721.1 h45
  text ".PRJ_Title" at 7210.54,-1854.43 h70
  text "DESIGNED FOR:" at 7160.54,-2022.1 h45
  text ".PRJ_Customer" at 7210.54,-2162.1 h70
  text "D" at -4599.46,-2230.1 h70
  text "D" at 10200.54,-2230.1 h70
  text "FILE NAME:" at 7160.54,-2322.1 h45
  text ".PCB_File_Name_No_Path" at 7210.54,-2442.1 h70
  text "Texas Instruments (TI) and/or its licensors do not warrant the accuracy or completeness of this specification" at 2191.04,-2603.94 h45
  text "ENGINEER:" at 7160.54,-2612.1 h45
  text "LAYOUT BY:" at 8665.54,-2612.1 h45
  text "or any information contained therein. TI and/or its licensors do not warrant that this design will meet" at 2146.06,-2716.6 h45
  text ".PRJ_Engineer" at 7210.54,-2767.09 h70
  text ".PCB_Layout" at 8716.04,-2767.09 h70
  text "the specifications, will be suitable for your application or fit for any particular purpose, or will operate in" at 2146.06,-2829.27 h45
  text ".Layer_Name" at -3605.96,-2857.09 h60
  text "ALTIUM DESIGNER VERSION:" at 8665.54,-2922.1 h45
  text "an implementation. TI and/or its licensors do not warrant that the design is production worthy. You should" at 2146.06,-2941.93 h45
  text "completely validate and test your design implementation to confirm the system functionality for your application." at 2191.04,-3054.6 h45
  text ".print_Scale" at 7210.54,-3055.43 h70
  text ".Application_BuildNumber" at 8716.04,-3055.43 h70
  text "1" at -3443.12,-3262.1 h70
  text "2" at -947.46,-3262.1 h70
  text "3" at 1541.89,-3262.1 h70
  text "4" at 4048.56,-3262.1 h70
  text "5" at 6547.54,-3262.1 h70
  text "6" at 9052.54,-3262.1 h70
M10 Fab Notes:
  drawing of 181 lines, arcs and shapes, not listed
  text "DESIGN INFORMATION" at 8195.06,4802.4 h60
  text "MIN. TRACK WIDTH:" at 7550.5,4622.4 h60
  text "6" at 8646.75,4622.4 h60
  text "MIL" at 8801.5,4622.4 h60
  text "MIN. CLEARANCE:" at 7550.5,4490.4 h60
  text "0.1" at 8586.75,4490.4 h60
  text "mm" at 8801.5,4490.4 h60
  text "MIN. VIA PAD SIZE:" at 7550.5,4358.4 h60
  text "22" at 8616.76,4358.4 h60
  text "MIL" at 8801.5,4358.4 h60
  text "0.05mm (2MIL)" at 8245.5,4216.69 h60
  text "MINIMUM ANNULAR RING" at 7221.27,4212.4 h60
  text "EXTERNAL" at 8953.5,4212.4 h60
  text "PER" at 7421.27,4094.4 h60
  text "IPC-D-275 CLASS 2 LEVEL C" at 7641.27,4094.4 h60
  text "MIL, HOLES" at 9129.5,3982.11 h60
  text "+/-" at 8737.04,3981.4 h60
  text "+/-" at 9591.04,3981.4 h60
  text "REGISTRATION TOLERANCES:" at 7221.27,3976.4 h60
  text "METAL" at 8421.04,3976.4 h60
  text "5" at 8997.25,3976.4 h60
  text "3" at 9830.25,3976.4 h60
  text "MIL" at 9946.5,3976.4 h60
  text "+/-" at 9591.04,3863.4 h60
  text "HOLE SIZE TOLERANCE (UNLESS OTHERWISE SPECIFIED):" at 7221.27,3858.4 h60
  text "3" at 9830.25,3858.4 h60
  text "MIL" at 9946.5,3858.4 h60
  text "MATERIAL:" at 7146.5,3648.94 h60
  text "FR-4 High Tg" at 8132.95,3508.61 h60
  text "FR-408" at 7567.51,3500.04 h60
  text "OTHER" at 9055.5,3500.04 h60
  text "X" at 7978.04,3496.4 h60
  text "THICKNESS:" at 7221.27,3333.04 h60
  text "X" at 7759.44,3333.04 h60
  text "OTHER" at 9242.55,3333.47 h60
  text "62 MIL (1.6mm) +/- 6MIL" at 7895.15,3331.66 h60
  text "TOLERANCE:" at 7221.27,3175.04 h60
  text "X" at 8060.58,3175.04 h60
  text "ANSI IPC-6012 TYPE 3 CLASS 2" at 8247.52,3175.04 h60
  text "OTHER +/-" at 8247.5,3019.04 h60
  text "BOW & TWIST:" at 7221.27,2862.04 h60
  text "X" at 8060.58,2862.04 h60
  text "ANSI IPC-6012 TYPE 3 CLASS 2" at 8247.52,2862.04 h60
  text "OTHER +/-" at 8247.5,2703.53 h60
  text "DRILLING:" at 7146.5,2565.04 h60
  text "REFERENCE:" at 7221.27,2448.04 h60
  text "X" at 7869.5,2448.04 h60
  text "AS SHOWN" at 8056.5,2448.04 h60
  text "X" at 8770.5,2448.04 h60
  text "NC_DRILL FILES" at 8907.5,2448.04 h60
  text "PTH COPPER THICKNESS:" at 7221.27,2290.04 h60
  text "X" at 8351.5,2290.04 h60
  text "20-30 um" at 8488.5,2290.04 h60
  text "OTHER" at 9205.5,2290.04 h60
  text "BOARD FINISH:" at 7146.5,2131.04 h60
  text "SILKSCREEN:" at 7301.73,2013.04 h60
  text "X" at 8250.5,2013.04 h60
  text "TOP" at 8376.5,2013.04 h60
  text "X" at 8760.5,2013.04 h60
  text "BOTTOM" at 8887.5,2013.04 h60
  text "SILKSCREEN COLOR:" at 7301.73,1846.04 h60
  text "X" at 8249.46,1846.04 h60
  text "WHITE" at 8376.5,1846.04 h60
  text "OTHER" at 8887.5,1846.04 h60
  text "X" at 8380.47,1686.84 h60
  text "GREEN" at 8507.5,1686.84 h60
  text "OTHER" at 9125.5,1686.84 h60
  text "SOLDER RESIST COLOR:" at 7301.73,1676.04 h60
  text "X" at 8380.47,1516.84 h60
  text "MATTE" at 8507.5,1516.84 h60
  text "SEMI-GLOSS" at 9125.04,1516.2 h60
  text "IMMERSION GOLD (ENIG)" at 8207.5,1328.32 h60
  text "ENEPIG" at 9545.04,1325.04 h60
  text "SURFACE FINISH:" at 7146.5,1324.04 h60
  text "X" at 8020.56,1324.04 h60
  text "HARD GOLD FINGERS" at 9226.94,1169 h60
  text "IMM. TIN/SILVER OR EQUIV" at 7476.04,1167.04 h60
  text "OTHER" at 8907.5,1167.04 h60
  text "X" at 8714.56,1151.04 h60
  text "ARRAY/PANEL:" at 7146.5,988.04 h60
  text "CUT AND TRIM PER M1 BOARD OUTLINE" at 8207.51,983.75 h60
  text "N.C. ROUTE" at 8207.5,832.04 h60
  text "X" at 8886.5,832.04 h60
  text "V. SCORE" at 9073.5,832.04 h60
  text "CERTIFICATION:" at 7146.5,695.04 h60
  text "MATERIALS AND WORKMANSHIP FOR ALL PCBS" at 7871.5,695.04 h60
  text "TO MEET OR EXCEED THE REQUIREMENTS OF:" at 7871.5,597.04 h60
  text "X" at 7498.01,460.53 h60
  text "ANSI IPC-A-600F CLASS ->" at 7637.01,460.53 h60
  text "X" at 9276.06,460.53 h60
  text "2" at 9395.01,460.54 h60
  text "1" at 9080.01,459.04 h60
  text "3" at 9749.01,459.04 h60
  text "X" at 8312.06,301.04 h60
  text "RoHS" at 8449.01,301.04 h60
  text "OTHER" at 9093.41,301.04 h60
  text "PER ORDER" at 9490.47,301.04 h60
  text "ALL BOARDS MUST MEET OR EXCEED UL94-V0 REQUIREMENTS." at 7174.04,135.4 h60
  text "PCB MUST BEAR THE UL94V-0 UL REGISTERED MATERIAL ID NUMBER" at 7174.04,15.4 h60
  text "ADDITIONAL REQUIREMENTS:" at 7146.5,-157.96 h60
  text "MICROSECTION:" at 7221.27,-272.96 h60
  text "YES" at 8127.01,-272.96 h60
  text "REQUIRED" at 8988.5,-429.11 h60
  text "BARE BOARD ELEC. TEST:" at 7221.27,-431.96 h60
  text "NONE" at 8527.01,-431.96 h60
  text "X" at 8861.5,-431.96 h60
  text "PER ORDER" at 9580.5,-431.96 h60
  text "X" at 7289,-703 h60
  text "ALL LAYERS 6.1 MIL WIDE, 6 MIL SPACE / TRACES REQUIRE 90 OHM DIFFERENTIAL IMPEDANCE" at 7494,-766 h60
  text "X" at 7291.92,-902.91 h60
  text "ALL LAYERS 6.2 MIL WIDE, 6 MIL SPACE / TRACES REQUIRE 90 OHM DIFFERENTIAL IMPEDANCE" at 7409,-953 h60
  text ".Layer_Name" at -3605.96,-2857.09 h60
M11 Gerber Information:
  lines w10: -4474.96,-2928.77 2125.04,-2928.77 ; -4474.96,-2725.43 2127.04,-2725.43 ; -4474.96,-2522.1 -4474.96,-3132.1 -469.96,-3132.1 2127.04,-3132.1 2127.04,-2522.1 -4474.46,-2522.1 -4474.46,-3132.1 -2898.96,-3132.1 ; -2009.96,-3132.1 -2009.96,-2522.1 ; -742.96,-2725.43 -742.96,-2522.1 ; 97.04,-2725.43 97.04,-2522.1 ; 719.04,-3138.6 719.04,-2935.77
  text "ALL ARTWORK VIEWED FROM TOP SIDE" at -4411.46,-2654.27 h60
  text "BOARD #:" at -1934.96,-2654.27 h60
  text ".PRJ_Number" at -1389.46,-2654.27 h60
  text "REV:" at -544.96,-2654.27 h60
  text ".PCB_Rev" at -253.46,-2654.27 h60
  text "SVN REV:" at 293.04,-2654.27 h60
  text ".VersionControl_RevNumber" at 799.04,-2654.27 h60
  text "LAYER NAME =" at -4411.46,-2857.09 h60
  text "TID #:" at -1934.96,-2857.6 h60
  text ".TID" at -1389.46,-2857.6 h60
  text "PLOT NAME =" at -4411.46,-3062.94 h60
  text ".plot_File_Name" at -3605.96,-3062.94 h60
  text "GENERATED    :" at -1932.96,-3062.94 h60
  text ".Print_Date" at -1063.46,-3062.94 h60
  text ".Print_Time" at -334.46,-3062.94 h60
  text "TEXAS INSTRUMENTS" at 930.04,-3062.94 h60
M12 Stackup:
  drawing of 399 lines, arcs and shapes, not listed
  text "Layer" at 925.67,5250 h60
  text "Name" at 1335.58,5250 h60
  text "Material" at 2545.23,5250 h60
  text "Thickness" at 3405,5250 h60
  text "Constant" at 4054.84,5250 h60
  text "Board Layer Stack" at 4624.7,5250 h60
  text "Top Overlay" at 1335.58,5130 h60
  text "Top Solder" at 1335.58,5010 h60
  text "Solder Resist" at 2545.23,5010 h60
  text "0.70mil" at 3405,5010 h60
  text "3.5" at 4054.84,5010 h60
  text "1" at 925.67,4890 h60
  text "Top Signal Layer" at 1335.58,4890 h60
  text "1.40mil" at 3405,4890 h60
  text "Dielectric1" at 1335.58,4770 h60
  text "FR-4 High Tg" at 2545.23,4770 h60
  text "7.00mil" at 3405,4770 h60
  text "4.2" at 4054.84,4770 h60
  text "2" at 925.67,4650 h60
  text "GND1" at 1335.58,4650 h60
  text "1.40mil" at 3405,4650 h60
  text "Dielectric2" at 1335.58,4530 h60
  text "FR-4 High Tg" at 2545.23,4530 h60
  text "14.00mil" at 3405,4530 h60
  text "4.2" at 4054.84,4530 h60
  text "3" at 925.67,4410 h60
  text "Mid Layer" at 1335.58,4410 h60
  text "1.40mil" at 3405,4410 h60
  text "Dielectric3" at 1335.58,4290 h60
  text "FR-4 High Tg" at 2545.23,4290 h60
  text "10.00mil" at 3405,4290 h60
  text "4.2" at 4054.84,4290 h60
  text "4" at 925.67,4170 h60
  text "PWR" at 1335.58,4170 h60
  text "1.40mil" at 3405,4170 h60
  text "Dielectric4" at 1335.58,4050 h60
  text "FR-4 High Tg" at 2545.23,4050 h60
  text "14.00mil" at 3405,4050 h60
  text "4.2" at 4054.84,4050 h60
  text "5" at 925.67,3930 h60
  text "GND2" at 1335.58,3930 h60
  text "1.40mil" at 3405,3930 h60
  text "Dielectric5" at 1335.58,3810 h60
  text "FR-4 High Tg" at 2545.23,3810 h60
  text "7.00mil" at 3405,3810 h60
  text "4.2" at 4054.84,3810 h60
  text "6" at 925.67,3690 h60
  text "Bottom Signal Layer" at 1335.58,3690 h60
  text "1.40mil" at 3405,3690 h60
  text "Bottom Solder" at 1335.58,3570 h60
  text "Solder Resist" at 2545.23,3570 h60
  text "0.70mil" at 3405,3570 h60
  text "3.5" at 4054.84,3570 h60
  text "Bottom Overlay" at 1335.58,3450 h60
  text ".Layer_Name" at -3605.96,-2857.09 h60
M13 Component Bodies Top:
  text ".Layer_Name" at -3605.96,-2857.09 h60
M14 Component Bodies Bottom:
  text ".Layer_Name" at -3605.96,-2857.09 h60
M15 Courtyards Top:
  text ".Layer_Name" at -3605.96,-2857.09 h60
M16 Courtyards Bottom:
  text ".Layer_Name" at -3605.96,-2857.09 h60
Drill Drawing:
  circle w10: c-3608.59,4050.33 r33.33
  circle w10: c-3608.59,3900.33 r20
  circle w10: c-3608.59,3900.33 r33.33
  lines w10: -290.05,248.71 ccw(c-285.04,248.71) -285.04,243.7 -99.05,243.7 ; -289.73,248.71 -289.73,1938 cw(c-284.73,1938) -284.73,1943 ; -285.04,1943 1736.68,1943.01 ; -98.59,243.24 -98.59,113.94 cw(c-132.57,113.92) -153.08,86.83 ccw(c-156.06,82.96) -156.1,87.84 -172.43,87.84 ccw(c-172.47,82.91) -175.98,86.37 ccw(c-172.43,82.73) -177.51,82.76 -177.51,4.84 ccw(c-172.51,4.83) -171.34,-0.04 -0.26,-0.04 -0.26,-231.05 ccw(c4.75,-231.05) 5.58,-236 917.19,-236 ccw(c917.19,-230.98) 922.21,-230.98 ccw(c917.45,-230.97) 921.99,-229.57 922,-35.08 922.1,-34.1 cw(c969.58,-34.49) 1017.07,-34.1 1017.07,-231.27 ccw(c1022.07,-231.28) 1018.53,-234.82 ccw(c1022.19,-231.22) 1022.14,-236.35 2059.9,-236.28 ccw(c2059.9,-231.26) 2064.91,-231.26 2064.84,-230.44 2064.84,-0.11 2247.07,-0.11 ccw(c2247.07,4.91) 2252.09,4.91 ccw(c2247.33,4.92) 2251.88,6.32 ; 1737.68,1943 cw(c1737.68,1761.34) 1837.68,1913.01 ccw(c1937.68,2064.67) 2037.68,1913.01 cw(c2137.68,1761.34) 2137.68,1943.01 ; 2139.68,1943 2360.68,1943.01 ; 2173.1,244.17 2173.1,114.71 ccw(c2207.08,114.83) 2227.58,87.73 ; 2173.11,244.19 2363.68,244.19 ; 2227.58,87.72 cw(c2230.59,83.8) 2230.61,88.74 2244.89,88.74 cw(c2246.88,84.13) 2251.88,84.13 2251.88,6.33 ; 2363.68,244.29 ccw(c2363.68,249.29) 2368.68,249.29 ; 2368.68,249.27 2368.68,1935.72 ; 2368.68,1935.72 ccw(c2362.6,1936.83) 2362.69,1943.01 cw(c2362.6,1936.82) 2368.68,1935.72 ; -3641.93,3417 -3608.59,3433.67 -3575.26,3417 -3591.93,3450.33 -3575.26,3483.67 -3608.59,3467 -3641.93,3483.67 -3625.26,3450.33 -3641.93,3417 ; -3641.93,3633.67 -3575.26,3633.67 -3608.59,3567 -3641.93,3633.67 ; -3641.93,3733.67 -3625.26,3733.67 -3625.26,3717 -3591.93,3717 -3591.93,3733.67 -3575.26,3733.67 -3575.26,3767 -3591.93,3767 -3591.93,3783.67 -3625.26,3783.67 -3625.26,3767 -3641.93,3767 -3641.93,3733.67 ; -3641.93,4233.67 -3575.26,4233.67 -3608.59,4167 -3641.93,4233.67 ; -3641.93,4333.67 -3625.26,4333.67 -3608.59,4317 -3591.93,4333.67 -3575.26,4333.67 -3591.93,4350.33 -3575.26,4367 -3591.93,4367 -3608.59,4383.67 -3625.26,4367 -3641.93,4367 -3625.26,4350.33 -3641.93,4333.67 ; -3641.93,4500.33 -3608.59,4467 -3575.26,4500.33 -3608.59,4533.67 -3641.93,4500.33 ; -3641.93,4617 -3575.26,4617 -3575.26,4683.67 -3641.93,4683.67 -3641.93,4617 ; -3641.93,4767 -3641.93,4783.67 -3625.26,4800.33 -3641.93,4817 -3641.93,4833.67 -3625.26,4833.67 -3608.59,4817 -3591.93,4833.67 -3575.26,4833.67 -3575.26,4817 -3591.93,4800.33 -3575.26,4783.67 -3575.26,4767 -3591.93,4767 -3608.59,4783.67 -3625.26,4767 -3641.93,4767 ; -3628.59,3620.33 -3588.59,3620.33 -3608.59,3580.33 -3628.59,3620.33
  lines w15: -3701.72,3372 -166.64,3372 ; -3701.72,4872 -166.64,4872 ; -3150.84,3222 -3150.84,5022 ; -2551,3222 -2551,5022 ; -1451.32,3222 -1451.32,5022 ; -945.44,3222 -945.44,5022 ; -3701.72,3222 -166.64,3222 -166.64,5022 -3701.72,5022 -3701.72,3222
  text "Symbol" at -3611.72,4917 h72
  text "Count" at -3105.84,4917 h72
  text "Hole Size" at -2506,4917 h72
  text "Plated" at -1406.32,4917 h72
  text "Hole Type" at -900.44,4917 h72
  text "2" at -3105.84,4767 h60
  text "7.87mil (0.200mm)" at -2506,4767 h60
  text "PTH" at -1406.32,4767 h60
  text "Round" at -900.44,4767 h60
  text "2" at -3105.84,4617 h60
  text "35.43mil (0.900mm)" at -2506,4617 h60
  text "NPTH" at -1406.32,4617 h60
  text "Round" at -900.44,4617 h60
  text "4" at -3105.84,4467 h60
  text "7.99mil (0.203mm)" at -2506,4467 h60
  text "PTH" at -1406.32,4467 h60
  text "Round" at -900.44,4467 h60
  text "4" at -3105.84,4317 h60
  text "23.62mil (0.600mm)" at -2506,4317 h60
  text "PTH" at -1406.32,4317 h60
  text "Slot" at -900.44,4317 h60
  text "10" at -3105.84,4167 h60
  text "35.04mil (0.890mm)" at -2506,4167 h60
  text "PTH" at -1406.32,4167 h60
  text "Round" at -900.44,4167 h60
  text "11" at -3105.84,4017 h60
  text "25.00mil (0.635mm)" at -2506,4017 h60
  text "PTH" at -1406.32,4017 h60
  text "Round" at -900.44,4017 h60
  text "14" at -3105.84,3867 h60
  text "15.75mil (0.400mm)" at -2506,3867 h60
  text "PTH" at -1406.32,3867 h60
  text "Round" at -900.44,3867 h60
  text "16" at -3105.84,3717 h60
  text "11.81mil (0.300mm)" at -2506,3717 h60
  text "PTH" at -1406.32,3717 h60
  text "Round" at -900.44,3717 h60
  text "142" at -3105.84,3567 h60
  text "9.84mil (0.250mm)" at -2506,3567 h60
  text "PTH" at -1406.32,3567 h60
  text "Round" at -900.44,3567 h60
  text "398" at -3105.84,3417 h60
  text "9.84mil (0.250mm)" at -2506,3417 h60
  text "PTH" at -1406.32,3417 h60
  text "Round" at -900.44,3417 h60
  text "603 Total" at -3105.84,3267 h60
  text "Slot definitions :" at -3611.72,3122.03 h60
  text "Routed Path Length" at -2579.03,3122.03 h60
  text "= Calculated from tool start centre position to tool end centre position." at -1476.36,3122.03 h60
  text "Hole Length" at -2579.03,3022.05 h60
  text "= Routed Path Length + Tool Size = Slot length as defined in the PCB layout" at -1886.23,3022.05 h60
  text ".Layer_Name" at -3605.22,-2856.09 h60

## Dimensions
-4182.96,-2398.6 to -3182.96,-2398.6 on M2 Board Dimensions
1642.94,-262 to 2025.94,-657 on M2 Board Dimensions
-317.06,1942 to -29.16,-237 on M2 Board Dimensions
2367.94,1745.72 to -293.06,1745.72 on M2 Board Dimensions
